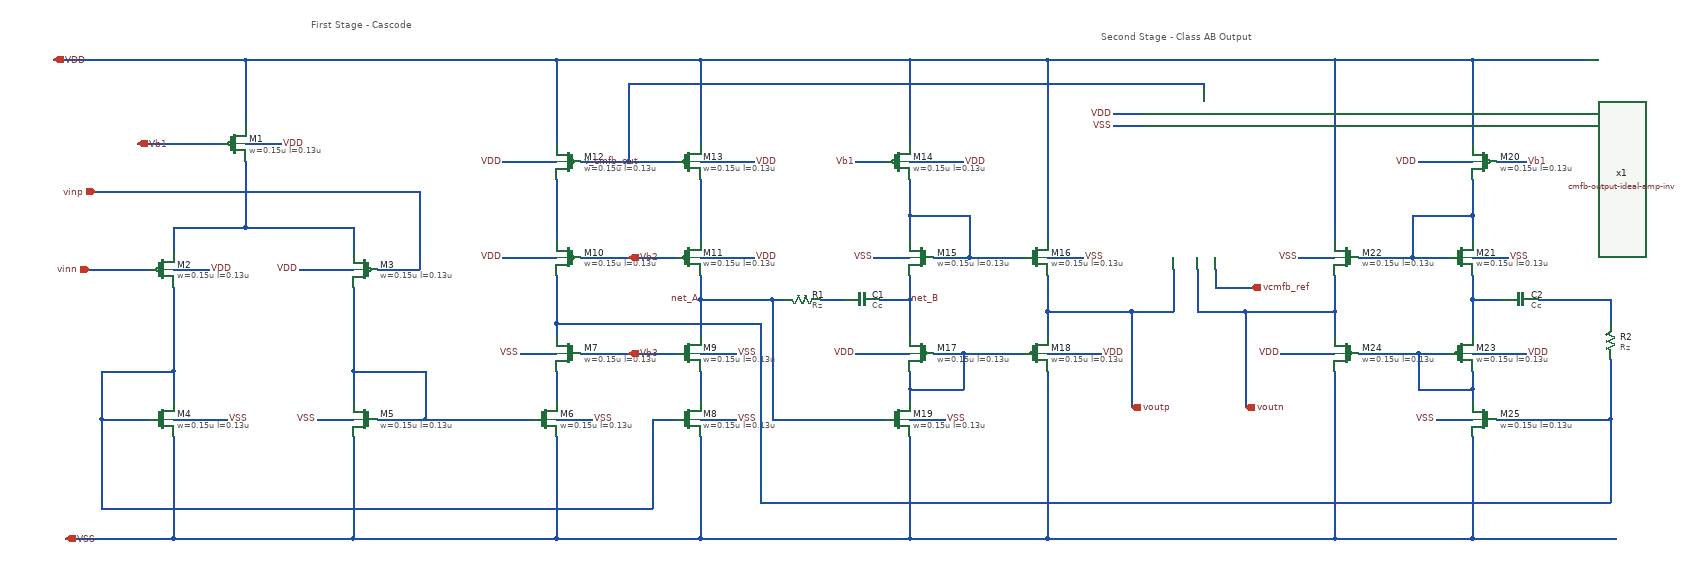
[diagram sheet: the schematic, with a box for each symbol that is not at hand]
v {xschem version=3.4.5 file_version=1.2
}
G {}
K {}
V {}
S {}
E {}
T {First Stage - Cascode} 810 -990 0 0 0.4 0.4 {}
T {Second Stage - Class AB Output} 2130 -970 0 0 0.4 0.4 {}
N 580 -640 700 -640 {
lab=#net1}
N 580 -640 580 -600 {
lab=#net1}
N 700 -640 880 -640 {
lab=#net1}
N 880 -640 880 -600 {
lab=#net1}
N 700 -750 700 -640 {
lab=#net1}
N 920 -570 990 -570 {
lab=vinp}
N 990 -700 990 -570 {
lab=vinp}
N 450 -700 990 -700 {
lab=vinp}
N 440 -570 540 -570 {
lab=vinn}
N 580 -570 640 -570 {
lab=VDD}
N 790 -570 880 -570 {
lab=VDD}
N 700 -780 760 -780 {
lab=VDD}
N 700 -920 700 -810 {
lab=VDD}
N 380 -920 700 -920 {
lab=VDD}
N 2040 -920 2520 -920 {
lab=VDD}
N 520 -780 660 -780 {
lab=Vb1}
N 580 -400 580 -350 {
lab=#net2}
N 880 -400 880 -350 {
lab=#net3}
N 820 -320 880 -320 {
lab=VSS}
N 580 -320 670 -320 {
lab=VSS}
N 580 -290 580 -120 {
lab=VSS}
N 400 -120 580 -120 {
lab=VSS}
N 880 -290 880 -120 {
lab=VSS}
N 580 -120 880 -120 {
lab=VSS}
N 460 -320 540 -320 {
lab=#net2}
N 460 -400 460 -320 {
lab=#net2}
N 460 -400 580 -400 {
lab=#net2}
N 580 -540 580 -400 {
lab=#net2}
N 880 -400 1000 -400 {
lab=#net3}
N 880 -540 880 -400 {
lab=#net3}
N 1000 -400 1000 -320 {
lab=#net3}
N 920 -320 1000 -320 {
lab=#net3}
N 1220 -400 1220 -350 {
lab=#net4}
N 1220 -320 1280 -320 {
lab=VSS}
N 1000 -320 1180 -320 {
lab=#net3}
N 1220 -290 1220 -120 {
lab=VSS}
N 880 -120 1220 -120 {
lab=VSS}
N 1160 -430 1220 -430 {
lab=VSS}
N 1460 -400 1460 -350 {
lab=#net5}
N 1460 -320 1520 -320 {
lab=VSS}
N 1460 -430 1520 -430 {
lab=VSS}
N 1460 -290 1460 -120 {
lab=VSS}
N 1220 -120 1460 -120 {
lab=VSS}
N 1260 -430 1420 -430 {
lab=Vb3}
N 1380 -320 1420 -320 {
lab=#net2}
N 1380 -320 1380 -170 {
lab=#net2}
N 460 -170 1380 -170 {
lab=#net2}
N 460 -320 460 -170 {
lab=#net2}
N 1130 -590 1220 -590 {
lab=VDD}
N 1460 -590 1550 -590 {
lab=VDD}
N 1260 -590 1420 -590 {
lab=Vb2}
N 1130 -750 1220 -750 {
lab=VDD}
N 1460 -750 1550 -750 {
lab=VDD}
N 1340 -750 1420 -750 {
lab=v_cmfb_out}
N 1220 -720 1220 -620 {
lab=#net6}
N 1460 -720 1460 -620 {
lab=#net7}
N 1340 -880 1340 -750 {
lab=v_cmfb_out}
N 1260 -750 1340 -750 {
lab=v_cmfb_out}
N 1340 -880 2300 -880 {
lab=v_cmfb_out}
N 1460 -920 1460 -780 {
lab=VDD}
N 1220 -920 1460 -920 {
lab=VDD}
N 1220 -920 1220 -780 {
lab=VDD}
N 700 -920 1220 -920 {
lab=VDD}
N 1460 -520 1460 -460 {
lab=net_A}
N 1220 -480 1220 -460 {
lab=#net8}
N 1220 -560 1220 -480 {
lab=#net8}
N 1810 -750 1900 -750 {
lab=VDD}
N 1810 -660 1810 -620 {
lab=#net9}
N 1810 -920 1810 -780 {
lab=VDD}
N 1460 -920 1810 -920 {
lab=VDD}
N 1720 -750 1770 -750 {
lab=Vb1}
N 1750 -590 1810 -590 {
lab=VSS}
N 2040 -590 2100 -590 {
lab=VSS}
N 1910 -590 2000 -590 {
lab=#net9}
N 2040 -920 2040 -620 {
lab=VDD}
N 1810 -920 2040 -920 {
lab=VDD}
N 1660 -520 1700 -520 {
lab=#net10}
N 1580 -520 1600 -520 {
lab=net_A}
N 1460 -560 1460 -520 {
lab=net_A}
N 1910 -660 1910 -590 {
lab=#net9}
N 1850 -590 1910 -590 {
lab=#net9}
N 1810 -660 1910 -660 {
lab=#net9}
N 1810 -720 1810 -660 {
lab=#net9}
N 1760 -520 1810 -520 {
lab=net_B}
N 1810 -560 1810 -520 {
lab=net_B}
N 1720 -430 1810 -430 {
lab=VDD}
N 1560 -480 1560 -180 {
lab=#net8}
N 1810 -520 1810 -460 {
lab=net_B}
N 2040 -430 2130 -430 {
lab=VDD}
N 2040 -400 2040 -120 {
lab=VSS}
N 1900 -430 2000 -430 {
lab=#net11}
N 1850 -430 1900 -430 {
lab=#net11}
N 1810 -370 1900 -370 {
lab=#net11}
N 1810 -370 1810 -350 {
lab=#net11}
N 1810 -290 1810 -120 {
lab=VSS}
N 1460 -120 1810 -120 {
lab=VSS}
N 1810 -400 1810 -370 {
lab=#net11}
N 1900 -430 1900 -370 {
lab=#net11}
N 1580 -520 1580 -320 {
lab=net_A}
N 1460 -520 1580 -520 {
lab=net_A}
N 1580 -320 1770 -320 {
lab=net_A}
N 1220 -480 1560 -480 {
lab=#net8}
N 1560 -180 2980 -180 {
lab=#net8}
N 2040 -500 2040 -460 {
lab=voutp}
N 1810 -120 2040 -120 {
lab=VSS}
N 1810 -320 1870 -320 {
lab=VSS}
N 2660 -750 2750 -750 {
lab=VDD}
N 2750 -660 2750 -620 {
lab=#net12}
N 2750 -920 2750 -780 {
lab=VDD}
N 2790 -750 2840 -750 {
lab=Vb1}
N 2750 -590 2810 -590 {
lab=VSS}
N 2460 -590 2520 -590 {
lab=VSS}
N 2560 -590 2650 -590 {
lab=#net12}
N 2520 -920 2520 -620 {
lab=VDD}
N 2650 -660 2650 -590 {
lab=#net12}
N 2650 -590 2710 -590 {
lab=#net12}
N 2650 -660 2750 -660 {
lab=#net12}
N 2750 -720 2750 -660 {
lab=#net12}
N 2750 -520 2800 -520 {
lab=#net13}
N 2750 -560 2750 -520 {
lab=#net13}
N 2750 -430 2840 -430 {
lab=VDD}
N 2750 -520 2750 -460 {
lab=#net13}
N 2430 -430 2520 -430 {
lab=VDD}
N 2520 -400 2520 -120 {
lab=VSS}
N 2560 -430 2660 -430 {
lab=#net14}
N 2660 -430 2710 -430 {
lab=#net14}
N 2660 -370 2750 -370 {
lab=#net14}
N 2750 -370 2750 -350 {
lab=#net14}
N 2750 -290 2750 -120 {
lab=VSS}
N 2750 -400 2750 -370 {
lab=#net14}
N 2660 -430 2660 -370 {
lab=#net14}
N 2790 -320 2980 -320 {
lab=#net8}
N 2520 -500 2520 -460 {
lab=voutn}
N 2690 -320 2750 -320 {
lab=VSS}
N 2040 -120 2520 -120 {
lab=VSS}
N 2520 -120 2750 -120 {
lab=VSS}
N 2750 -920 2940 -920 {
lab=VDD}
N 2520 -920 2750 -920 {
lab=VDD}
N 2750 -120 2990 -120 {
lab=VSS}
N 2980 -320 2980 -180 {
lab=#net8}
N 2980 -420 2980 -320 {
lab=#net8}
N 2860 -520 2980 -520 {
lab=#net15}
N 2980 -520 2980 -480 {
lab=#net15}
N 2370 -500 2520 -500 {
lab=voutn}
N 2520 -560 2520 -500 {
lab=voutn}
N 2040 -500 2180 -500 {
lab=voutp}
N 2040 -560 2040 -500 {
lab=voutp}
N 2180 -500 2180 -340 {
lab=voutp}
N 2370 -500 2370 -340 {
lab=voutn}
N 2290 -500 2370 -500 {
lab=voutn}
N 2290 -570 2290 -500 {
lab=voutn}
N 2180 -500 2250 -500 {
lab=voutp}
N 2250 -570 2250 -500 {
lab=voutp}
N 2320 -570 2320 -540 {
lab=vcmfb_ref}
N 2320 -540 2380 -540 {
lab=vcmfb_ref}
N 2150 -830 2200 -830 {
lab=VDD}
N 2150 -810 2200 -810 {
lab=VSS}
N 2300 -880 2300 -870 {
lab=v_cmfb_out}
C {devices/title.sym} 180 -40 0 0 {name=l5 author="Copyright 2026 MacAnalog Research Group"}
C {sg13g2_pr/sg13_lv_pmos.sym} 680 -780 0 0 {name=M1
l=0.13u
w=0.15u
ng=1
m=1
model=sg13_lv_pmos
spiceprefix=X
}
C {sg13g2_pr/sg13_lv_pmos.sym} 560 -570 0 0 {name=M2
l=0.13u
w=0.15u
ng=1
m=1
model=sg13_lv_pmos
spiceprefix=X
}
C {sg13g2_pr/sg13_lv_pmos.sym} 900 -570 0 1 {name=M3
l=0.13u
w=0.15u
ng=1
m=1
model=sg13_lv_pmos
spiceprefix=X
}
C {iopin.sym} 380 -920 0 1 {name=p1 lab=VDD}
C {iopin.sym} 520 -780 0 1 {name=p2 lab=Vb1}
C {ipin.sym} 450 -700 0 0 {name=p3 lab=vinp}
C {ipin.sym} 440 -570 0 0 {name=p4 lab=vinn}
C {sg13g2_pr/sg13_lv_nmos.sym} 560 -320 0 0 {name=M4
l=0.13u
w=0.15u
ng=1
m=1
model=sg13_lv_nmos
spiceprefix=X
}
C {sg13g2_pr/sg13_lv_nmos.sym} 900 -320 0 1 {name=M5
l=0.13u
w=0.15u
ng=1
m=1
model=sg13_lv_nmos
spiceprefix=X
}
C {iopin.sym} 400 -120 0 1 {name=p5 lab=VSS}
C {lab_pin.sym} 820 -320 0 0 {name=p6 sig_type=std_logic lab=VSS}
C {lab_pin.sym} 670 -320 0 1 {name=p7 sig_type=std_logic lab=VSS}
C {lab_pin.sym} 640 -570 0 1 {name=p8 sig_type=std_logic lab=VDD}
C {lab_pin.sym} 790 -570 0 0 {name=p9 sig_type=std_logic lab=VDD}
C {lab_pin.sym} 760 -780 0 1 {name=p10 sig_type=std_logic lab=VDD}
C {sg13g2_pr/sg13_lv_nmos.sym} 1200 -320 0 0 {name=M6
l=0.13u
w=0.15u
ng=1
m=1
model=sg13_lv_nmos
spiceprefix=X
}
C {lab_pin.sym} 1280 -320 0 1 {name=p11 sig_type=std_logic lab=VSS}
C {sg13g2_pr/sg13_lv_nmos.sym} 1240 -430 0 1 {name=M7
l=0.13u
w=0.15u
ng=1
m=1
model=sg13_lv_nmos
spiceprefix=X
}
C {lab_pin.sym} 1160 -430 0 0 {name=p12 sig_type=std_logic lab=VSS}
C {sg13g2_pr/sg13_lv_nmos.sym} 1440 -320 0 0 {name=M8
l=0.13u
w=0.15u
ng=1
m=1
model=sg13_lv_nmos
spiceprefix=X
}
C {lab_pin.sym} 1520 -320 0 1 {name=p13 sig_type=std_logic lab=VSS}
C {sg13g2_pr/sg13_lv_nmos.sym} 1440 -430 0 0 {name=M9
l=0.13u
w=0.15u
ng=1
m=1
model=sg13_lv_nmos
spiceprefix=X
}
C {lab_pin.sym} 1520 -430 0 1 {name=p14 sig_type=std_logic lab=VSS}
C {iopin.sym} 1340 -430 3 1 {name=p15 lab=Vb3}
C {sg13g2_pr/sg13_lv_pmos.sym} 1240 -590 0 1 {name=M10
l=0.13u
w=0.15u
ng=1
m=1
model=sg13_lv_pmos
spiceprefix=X
}
C {lab_pin.sym} 1130 -590 0 0 {name=p16 sig_type=std_logic lab=VDD}
C {sg13g2_pr/sg13_lv_pmos.sym} 1440 -590 0 0 {name=M11
l=0.13u
w=0.15u
ng=1
m=1
model=sg13_lv_pmos
spiceprefix=X
}
C {lab_pin.sym} 1550 -590 0 1 {name=p17 sig_type=std_logic lab=VDD}
C {lab_pin.sym} 1460 -520 0 0 {name=p18 sig_type=std_logic lab=net_A}
C {sg13g2_pr/sg13_lv_pmos.sym} 1240 -750 0 1 {name=M12
l=0.13u
w=0.15u
ng=1
m=1
model=sg13_lv_pmos
spiceprefix=X
}
C {lab_pin.sym} 1130 -750 0 0 {name=p19 sig_type=std_logic lab=VDD}
C {sg13g2_pr/sg13_lv_pmos.sym} 1440 -750 0 0 {name=M13
l=0.13u
w=0.15u
ng=1
m=1
model=sg13_lv_pmos
spiceprefix=X
}
C {lab_pin.sym} 1550 -750 0 1 {name=p20 sig_type=std_logic lab=VDD}
C {iopin.sym} 1340 -590 3 1 {name=p21 lab=Vb2}
C {lab_pin.sym} 1360 -750 1 1 {name=p22 sig_type=std_logic lab=v_cmfb_out}
C {sg13g2_pr/sg13_lv_pmos.sym} 1790 -750 0 0 {name=M14
l=0.13u
w=0.15u
ng=1
m=1
model=sg13_lv_pmos
spiceprefix=X
}
C {lab_pin.sym} 1900 -750 0 1 {name=p23 sig_type=std_logic lab=VDD}
C {lab_pin.sym} 1720 -750 0 0 {name=p24 sig_type=std_logic lab=Vb1}
C {sg13g2_pr/sg13_lv_nmos.sym} 1830 -590 0 1 {name=M15
l=0.13u
w=0.15u
ng=1
m=1
model=sg13_lv_nmos
spiceprefix=X
}
C {lab_pin.sym} 1750 -590 0 0 {name=p25 sig_type=std_logic lab=VSS}
C {sg13g2_pr/sg13_lv_nmos.sym} 2020 -590 0 0 {name=M16
l=0.13u
w=0.15u
ng=1
m=1
model=sg13_lv_nmos
spiceprefix=X
}
C {lab_pin.sym} 2100 -590 0 1 {name=p26 sig_type=std_logic lab=VSS}
C {capa.sym} 1730 -520 1 0 {name=C1
m=1
value=Cc
footprint=1206
device="ceramic capacitor"}
C {res.sym} 1630 -520 1 0 {name=R1
value=Rz
footprint=1206
device=resistor
m=1}
C {sg13g2_pr/sg13_lv_pmos.sym} 1830 -430 0 1 {name=M17
l=0.13u
w=0.15u
ng=1
m=1
model=sg13_lv_pmos
spiceprefix=X
}
C {lab_pin.sym} 1720 -430 0 0 {name=p27 sig_type=std_logic lab=VDD}
C {sg13g2_pr/sg13_lv_pmos.sym} 2020 -430 0 0 {name=M18
l=0.13u
w=0.15u
ng=1
m=1
model=sg13_lv_pmos
spiceprefix=X
}
C {lab_pin.sym} 2130 -430 0 1 {name=p28 sig_type=std_logic lab=VDD}
C {sg13g2_pr/sg13_lv_nmos.sym} 1790 -320 0 0 {name=M19
l=0.13u
w=0.15u
ng=1
m=1
model=sg13_lv_nmos
spiceprefix=X
}
C {lab_pin.sym} 1870 -320 0 1 {name=p29 sig_type=std_logic lab=VSS}
C {lab_pin.sym} 1810 -520 0 1 {name=p30 sig_type=std_logic lab=net_B}
C {sg13g2_pr/sg13_lv_pmos.sym} 2770 -750 0 1 {name=M20
l=0.13u
w=0.15u
ng=1
m=1
model=sg13_lv_pmos
spiceprefix=X
}
C {lab_pin.sym} 2660 -750 0 0 {name=p31 sig_type=std_logic lab=VDD}
C {lab_pin.sym} 2840 -750 0 1 {name=p32 sig_type=std_logic lab=Vb1}
C {sg13g2_pr/sg13_lv_nmos.sym} 2730 -590 0 0 {name=M21
l=0.13u
w=0.15u
ng=1
m=1
model=sg13_lv_nmos
spiceprefix=X
}
C {lab_pin.sym} 2810 -590 0 1 {name=p33 sig_type=std_logic lab=VSS}
C {sg13g2_pr/sg13_lv_nmos.sym} 2540 -590 0 1 {name=M22
l=0.13u
w=0.15u
ng=1
m=1
model=sg13_lv_nmos
spiceprefix=X
}
C {lab_pin.sym} 2460 -590 0 0 {name=p34 sig_type=std_logic lab=VSS}
C {capa.sym} 2830 -520 3 1 {name=C2
m=1
value=Cc
footprint=1206
device="ceramic capacitor"}
C {sg13g2_pr/sg13_lv_pmos.sym} 2730 -430 0 0 {name=M23
l=0.13u
w=0.15u
ng=1
m=1
model=sg13_lv_pmos
spiceprefix=X
}
C {lab_pin.sym} 2840 -430 0 1 {name=p35 sig_type=std_logic lab=VDD}
C {sg13g2_pr/sg13_lv_pmos.sym} 2540 -430 0 1 {name=M24
l=0.13u
w=0.15u
ng=1
m=1
model=sg13_lv_pmos
spiceprefix=X
}
C {lab_pin.sym} 2430 -430 0 0 {name=p36 sig_type=std_logic lab=VDD}
C {sg13g2_pr/sg13_lv_nmos.sym} 2770 -320 0 1 {name=M25
l=0.13u
w=0.15u
ng=1
m=1
model=sg13_lv_nmos
spiceprefix=X
}
C {lab_pin.sym} 2690 -320 0 0 {name=p37 sig_type=std_logic lab=VSS}
C {res.sym} 2980 -450 2 0 {name=R2
value=Rz
footprint=1206
device=resistor
m=1}
C {opin.sym} 2180 -340 0 0 {name=p39 lab=voutp}
C {opin.sym} 2370 -340 0 0 {name=p40 lab=voutn}
C {shared/ideal/cmfb-output-ideal-amp-inv.sym} 2360 -590 3 0 {name=x1}
C {lab_pin.sym} 2150 -830 0 0 {name=p38 sig_type=std_logic lab=VDD}
C {lab_pin.sym} 2150 -810 0 0 {name=p41 sig_type=std_logic lab=VSS}
C {ipin.sym} 2380 -540 0 1 {name=p42 lab=vcmfb_ref}
